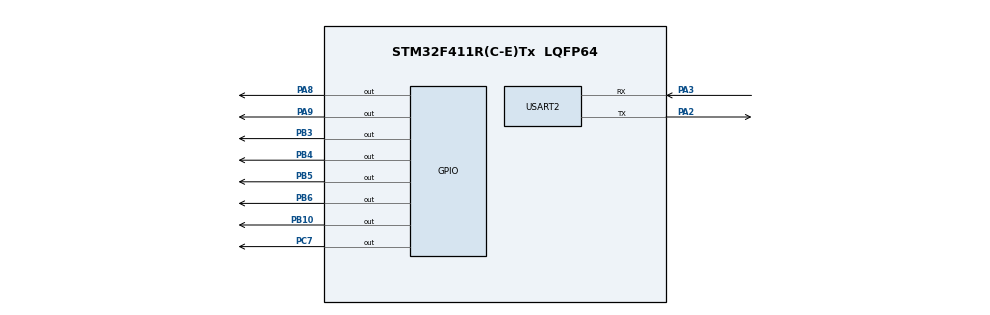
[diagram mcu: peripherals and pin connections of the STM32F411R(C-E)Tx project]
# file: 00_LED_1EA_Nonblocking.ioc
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Mcu.Family=STM32F4
Mcu.Name=STM32F411R(C-E)Tx
Mcu.Package=LQFP64
NVIC.PriorityGroup=NVIC_PRIORITYGROUP_4
PA13.Mode=Serial_Wire
PA13.Signal=SYS_JTMS-SWDIO
PA14.Mode=Serial_Wire
PA14.Signal=SYS_JTCK-SWCLK
PA2.Mode=Asynchronous
PA2.Signal=USART2_TX
PA3.Mode=Asynchronous
PA3.Signal=USART2_RX
PA8.Signal=GPIO_Output
PA9.Signal=GPIO_Output
PB10.Signal=GPIO_Output
PB3.Signal=GPIO_Output
PB4.Signal=GPIO_Output
PB5.Signal=GPIO_Output
PB6.Signal=GPIO_Output
PC14-OSC32_IN.Mode=LSE-External-Clock-Source
PC14-OSC32_IN.Signal=RCC_OSC32_IN
PC15-OSC32_OUT.Mode=LSE-External-Clock-Source
PC15-OSC32_OUT.Signal=RCC_OSC32_OUT
PC7.Signal=GPIO_Output
PH0\ -\ OSC_IN.Mode=HSE-External-Clock-Source
PH0\ -\ OSC_IN.Signal=RCC_OSC_IN
PH1\ -\ OSC_OUT.Mode=HSE-External-Clock-Source
PH1\ -\ OSC_OUT.Signal=RCC_OSC_OUT
ProjectManager.HeapSize=0x200
ProjectManager.StackSize=0x400
ProjectManager.TargetToolchain=STM32CubeIDE
RCC.48MHZClocksFreq_Value=100000000
RCC.AHBFreq_Value=16000000
RCC.APB1Freq_Value=16000000
RCC.APB2Freq_Value=16000000
RCC.CortexFreq_Value=16000000
RCC.HSE_VALUE=4000000
RCC.HSI_VALUE=16000000
RCC.LSE_VALUE=32768
RCC.PLLM=4
RCC.PLLN=100
RCC.SYSCLKFreq_VALUE=16000000
RCC.VCOOutputFreq_Value=400000000
USART2.VirtualMode=VM_ASYNC
board=custom

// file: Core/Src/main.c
/* USER CODE BEGIN Header */
/**
  ******************************************************************************
  * @file           : main.c
  * @brief          : Main program body
  ******************************************************************************
  * @attention
  *
  * Copyright (c) 2026 STMicroelectronics.
  * All rights reserved.
  *
  * This software is licensed under terms that can be found in the LICENSE file
  * in the root directory of this software component.
  * If no LICENSE file comes with this software, it is provided AS-IS.
  *
  ******************************************************************************
  */
/* USER CODE END Header */
#include "main.h"
#include "usart.h"
#include "gpio.h"

/* USER CODE BEGIN PTD */

typedef enum
{
    LED_OFF,
    LED_ON
}LED_STATE;

typedef struct
{
    GPIO_TypeDef    *port;
    uint16_t        number;
    uint32_t        interval;
    LED_STATE       state;
    uint32_t        lastTick;
}LED_CONTROL;

void updateLed(LED_CONTROL *led)
{
    uint32_t currTick = HAL_GetTick();

    if(currTick - led->lastTick >= led->interval)
    {
        led->lastTick = currTick;

        if(led->state == LED_OFF)
        {
            HAL_GPIO_WritePin(led->port, led->number, 1);
            led->state = LED_ON;
        }
        else
        {
            HAL_GPIO_WritePin(led->port, led->number, 0);
            led->state = LED_OFF;
        }
    }
}

/* USER CODE END PTD */

void SystemClock_Config(void);

int main(void)
{

  /* MCU Configuration--------------------------------------------------------*/

  /* Reset of all peripherals, Initializes the Flash interface and the Systick. */
  HAL_Init();

  /* Configure the system clock */
  SystemClock_Config();

  /* Initialize all configured peripherals */
  MX_GPIO_Init();
  MX_USART2_UART_Init();
  /* USER CODE BEGIN 2 */

  LED_CONTROL led1 = {GPIOA, GPIO_PIN_8, 200, LED_OFF, 0};
  LED_CONTROL led2 = {GPIOA, GPIO_PIN_9, 1000, LED_OFF, 0};

  /* USER CODE END 2 */

  /* Infinite loop */
  /* USER CODE BEGIN WHILE */
  while (1)
  {
      updateLed(&led1);
      updateLed(&led2);

    /* USER CODE END WHILE */

  }
}

void SystemClock_Config(void)
{
  RCC_OscInitTypeDef RCC_OscInitStruct = {0};
  RCC_ClkInitTypeDef RCC_ClkInitStruct = {0};

  /** Configure the main internal regulator output voltage
  */
  __HAL_RCC_PWR_CLK_ENABLE();
  __HAL_PWR_VOLTAGESCALING_CONFIG(PWR_REGULATOR_VOLTAGE_SCALE1);

  /** Initializes the RCC Oscillators according to the specified parameters
  * in the RCC_OscInitTypeDef structure.
  */
  RCC_OscInitStruct.OscillatorType = RCC_OSCILLATORTYPE_HSE;
  RCC_OscInitStruct.HSEState = RCC_HSE_BYPASS;
  RCC_OscInitStruct.PLL.PLLState = RCC_PLL_ON;
  RCC_OscInitStruct.PLL.PLLSource = RCC_PLLSOURCE_HSE;
  RCC_OscInitStruct.PLL.PLLM = 4;
  RCC_OscInitStruct.PLL.PLLN = 100;
  RCC_OscInitStruct.PLL.PLLP = RCC_PLLP_DIV2;
  RCC_OscInitStruct.PLL.PLLQ = 4;
  if (HAL_RCC_OscConfig(&RCC_OscInitStruct) != HAL_OK)
  {
    Error_Handler();
  }

  /** Initializes the CPU, AHB and APB buses clocks
  */
  RCC_ClkInitStruct.ClockType = RCC_CLOCKTYPE_HCLK|RCC_CLOCKTYPE_SYSCLK
                              |RCC_CLOCKTYPE_PCLK1|RCC_CLOCKTYPE_PCLK2;
  RCC_ClkInitStruct.SYSCLKSource = RCC_SYSCLKSOURCE_PLLCLK;
  RCC_ClkInitStruct.AHBCLKDivider = RCC_SYSCLK_DIV1;
  RCC_ClkInitStruct.APB1CLKDivider = RCC_HCLK_DIV2;
  RCC_ClkInitStruct.APB2CLKDivider = RCC_HCLK_DIV1;

  if (HAL_RCC_ClockConfig(&RCC_ClkInitStruct, FLASH_LATENCY_3) != HAL_OK)
  {
    Error_Handler();
  }
}

void Error_Handler(void)
{
  __disable_irq();
  while (1)
  {
  }
}
